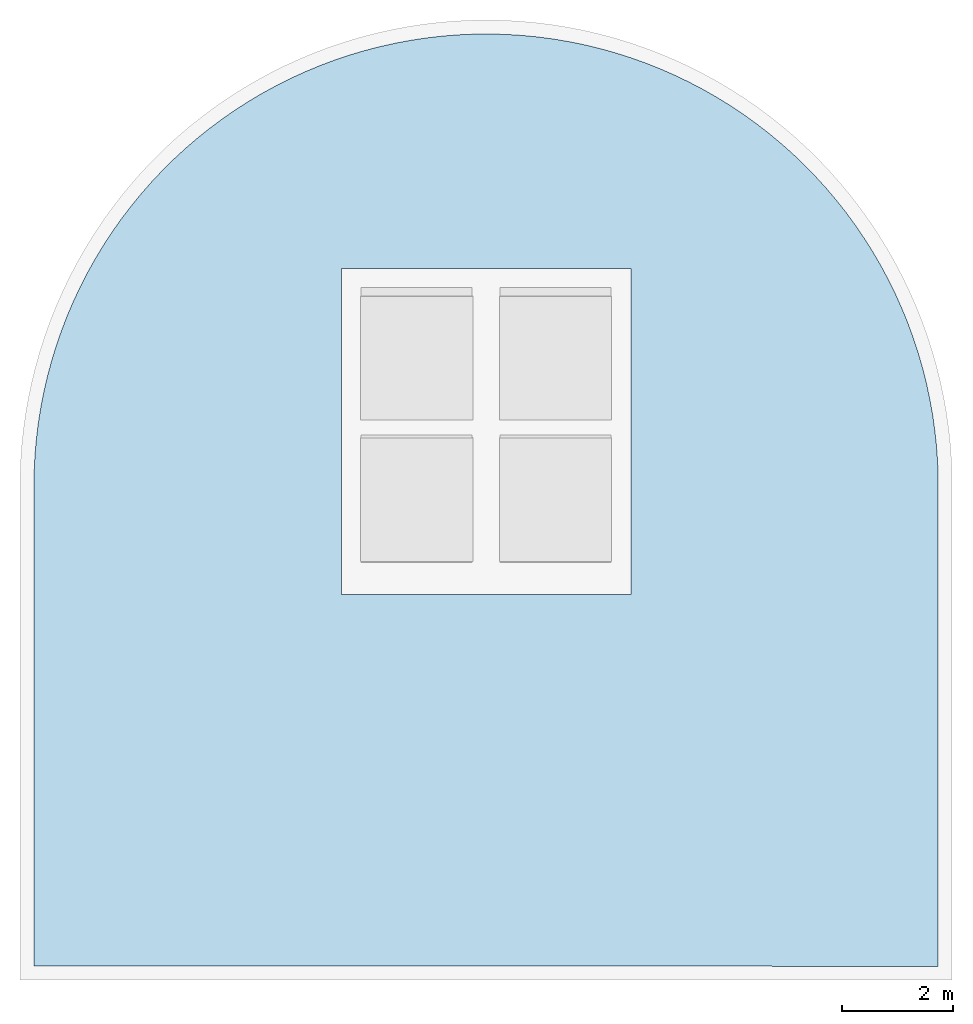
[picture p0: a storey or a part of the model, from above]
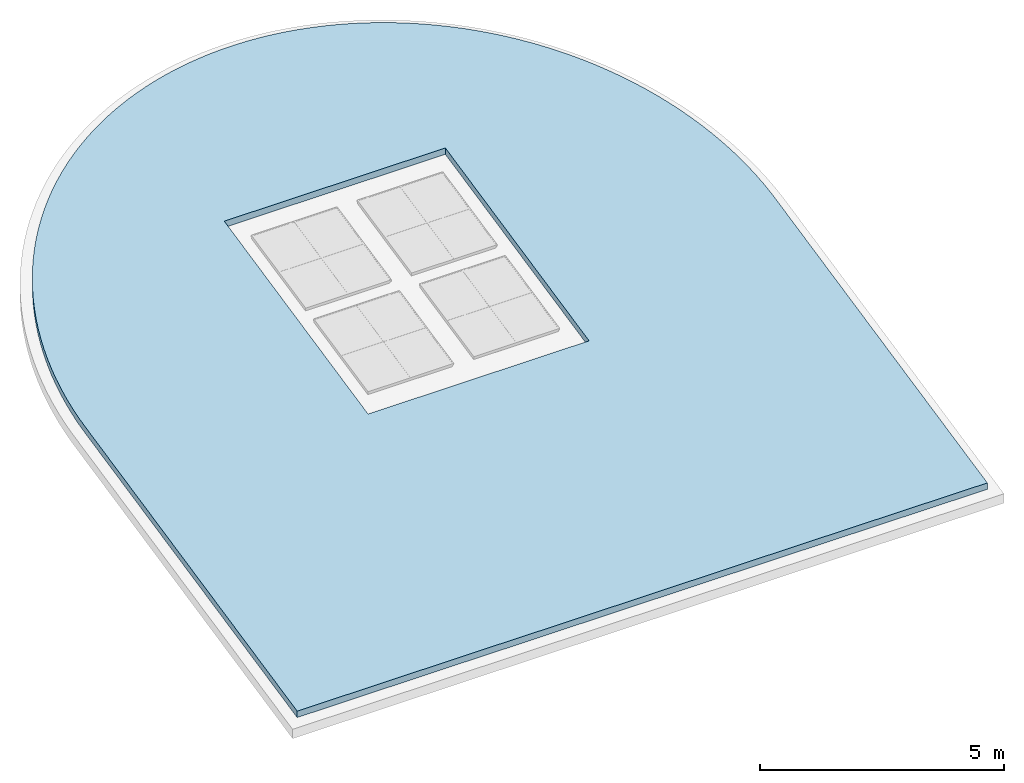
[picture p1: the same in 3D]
Properties of the parts of a building model (IFC4)

# File
Description: ViewDefinition [ReferenceView_V1.2], ExchangeRequirement [Architecture], Option [Elements to export: Visible elements (on all stories)], Option [Partial Structure Display: Entire Model], Option [IFC Domain: All], Option [Structural Function: All Elements], Option [Convert Grid elements: On], Option [Convert IFC Annotations and Archicad 2D elements: Off], Option [Convert 2D symbols of Doors and Windows: Off], Option [Export geometries that Participates in Collision Detection only: On], Option [Split complex elements: Off], Option [Material Preservation: Explode where necessary], Option [IFC Model position: Survey Point and Project Origin], Option [Curtain Wall export mode: Single Element], Option [Railing export mode: Single Element], Option [Stair export mode: Single Element], Option [Properties To Export: All properties], Option [Space containment: On], Option [IFC Domain For Space Containment: All], Option [Geometry to type objects: Off], Option [Element Properties: Off], Option [Building Material Properties: Off], Option [Element Parameters: Off], Option [Component Parameters: Off], Option [IFC Base Quantities: On], Option [Door Window Parameters: On], Option [IFC Space boundaries: On], Option [Archicad Zone Categories as IFC Space classification data: Off], Option [Element Classifications: Off]
File name: C:\Users\micel\OneDrive\Dokumenty\ŠKOLA\!!4.LS!!\BAKALÁŘKA\Publikace\Nová složka\LES24-PST-ZZ-M3-Obalka_budovy.ifc
Time: 2024-05-24T10:02:17
Author: Architect
Organization: Building Designer Office
Written by: DDS_IFC v3.0
Made in: IFC file generated by Graphisoft Archicad 27.0.0 CZE FULL Windows version (IFC add-on version: 3001 CZE FULL).
Authorization: The authorising person

# IfcProject, Univerzitní lezecké centrum
Description: BIM projekt - bakalářská práce

# IfcSite, Exteriér
RefLatitude: 50, 1, 18, 339575; RefLongitude: 15, 46, 11, 568244; RefElevation: 221783 mm
Qto_SiteBaseQuantities - GrossPerimeter: 0 mm; GrossArea: 3562 m2

# IfcBuilding, Univerzitní lezecké centrum
Qto_BuildingBaseQuantities - GrossFloorArea: 0 m2

# IfcBuildingStorey: Podlaží:0,000 (6)
In: Univerzitní lezecké centrum
Qto_BuildingStoreyBaseQuantities - GrossFloorArea: 0 m2
Name | LongName | Elevation (mm) | NetHeight (mm) = GrossHeight (mm)
1.PP | 1.PP | -3350 | 3350
2.NP | 2.NP | 3200 | 3200
3.NP | 3.NP | 6400 | 3200
1.NP | 1.NP | 0 | 3200
4.NP | 4.NP | 9600 | 3200
Střecha | Střecha | 12800 | 8000

# IfcCurtainWall: Typ lehkého obvodového pláště (8)
Pset_CurtainWallCommon - Status: EXISTING
Parametry - Druh zasklení: Izolační trojsklo, Ug=0,6 W/m2K; Bezpečnostní; Materiál okna: Hliníkové LOP; Barva rámu: Celadonově zelená RAL 6019
Pset_ManufacturerOccurrence - AcquisitionDate: DD.MM.RRRR
Qto_CurtainWallQuantities - Height: 2500 mm
Name | In | Material | Způsob otevírání | Width (mm) | Length (mm) | GrossSideArea (m2) = NetSideArea (m2)
4 x LOP01 | 1.NP | Sklo (4), Hliník (12) | Pevné | 50 | 2507.41 | 6.26851
2 x LOP01 | 1.NP | Sklo (4), Hliník (13) | Sklápěcí | 50 | 2507.41 | 6.26851
LOP01 | 1.NP | Hliník (22), Sklo (8), Ocel - nerez | Otočné | 50 | 2530.4 | 6.32599
LOP01 | 3.NP | Sklo (6), Hliník (17), Ocel - nerez | Otočné | 300 | 4500.17 | 11.2504

# IfcOpeningElement (33)
Name | In | Depth (mm) | Height (mm) | Width (mm) | Area (m2) | Volume (m3)
 | 1.PP | 160 | 0 | 0 | 0 | 0
 | 1.NP | 200 | 2200 | 1500 | 3.3 | 0
7 x  | 1.NP | 200 | 0 | 0 | 0 | 0
2 x Pr01 | 2.NP | 200 | 740 | 940 | 0.6956 | 0.13912 | Pset_OpeningElementCommon - Status: EXISTING
13 x  | 3.NP | 200 | 0 | 0 | 0 | 0
Pr02 | 3.NP | 200 | 830 | 930 | 0.7719 | 0.15438 | Pset_OpeningElementCommon - Status: EXISTING
Pr03 | 3.NP | 200 | 575 | 810.473 | 0.466022 | 0.0930961 | Pset_OpeningElementCommon - Status: EXISTING
2 x  | 4.NP | 200 | 0 | 0 | 0 | 0
Pr04 | 4.NP | 200 | 245.826 | 810.473 | 0.199235 | 0.039847 | Pset_OpeningElementCommon - Status: EXISTING
4 x O05 | Střecha |  | 2250 | 2000 | 4.5 | 1.0215

# IfcSlab: !Podlaha spádovaná - terasy - TI + HI vrstva 166 (8)
In: 4.NP
Type - PredefinedType: ROOF
Description: Desky z expandovaného pěnového polystyrenu, napětí v tlaku při 10% deformaci 150 kPa, součinitel tepelné vodivosti 0,035 W/mK; Material: TPO fólie ochranná, Geotextilie 200 g/m2, Hydroizolace - TPO fólie, Tepelná izolace - polystyren EPS podlahy
Parametry - Součinitel tepelné vodivosti: 0,035 W/mK; Objemová hmotnost: 25 kg/m3
Pset_SlabCommon - Status: EXISTING; LoadBearing: yes
Qto_SlabBaseQuantities - Width: 166 mm; TPO fólie ochranná, Width: 2 mm; Geotextilie 200 g/m2, Width: 2 mm; Hydroizolace - TPO fólie, Width: 2 mm; Tepelná izolace - polystyren EPS podlahy, Width: 160 mm
Pset_ManufacturerOccurrence - AcquisitionDate: DD.MM.RRRR
Name | Perimeter (mm) | GrossArea (m2) = NetArea (m2) | GrossVolume (m3) = NetVolume (m3)
 | 21271.8 | 19.4968 | 3.23647
 | 10319.8 | 2.0388 | 0.338443
 | 10319.2 | 2.03883 | 0.338447
 | 16973.6 | 14.4215 | 2.39397
 | 12627.2 | 9.72822 | 1.61489
 | 21273.1 | 19.4974 | 3.23657
S02 | 16978.1 | 14.427 | 2.39489
 | 12627.4 | 9.72817 | 1.61488

# IfcSlab: !Podlaha spádovaná - terasy - podložky + dlažba 135, S02
In: 4.NP
Type - PredefinedType: FLOOR
Description: Mrazuvzdorná betonová dlažba z vybrolisovaného betonu, hmotnost 111 kg/m2, rozměr 400x400 mm na podložkách: nastavitelné terčové podložky, kladeny na přířez HI; Material: Betonová dlažba, Rektifikální podložky
Pset_ManufacturerOccurrence - AcquisitionDate: DD.MM.RRRR
Qto_SlabBaseQuantities - Width: 135 mm; Perimeter: 40727.7 mm; GrossArea: 97.0699 m2; NetArea: 88.2021 m2; GrossVolume: 9.45602 m3; NetVolume: 8.25886 m3; Betonová dlažba, Width: 50 mm; Rektifikální podložky, Width: 85 mm
Pset_SlabCommon - Status: EXISTING; LoadBearing: yes

# IfcSlab: !Podlaha spádovaná - terasy - spádová vrstva EPS 205, S02
In: 4.NP
Type - PredefinedType: FLOOR
Description: Spádové klíny z expandovaného pěnového polystyrenu ve spádu 2%, základní rozměr desky 1x1 m, součinitel tepelné vodivosti 0,035 W/ mK, napětí v tlaku při 10% deformaci 150 kPa; Material: Tepelná izolace - polystyren EPS spádová vrstva, Parozábrana - modifikovaný asfaltový pás samolepící, Penetrační nátěr asfaltový
Parametry - Součinitel tepelné vodivosti: 0,035 W/ mK; Tloušťka: 25 kg/m3
Pset_SlabCommon - Status: EXISTING; LoadBearing: yes
Qto_SlabBaseQuantities - Width: 205 mm; Perimeter: 41132.7 mm; GrossArea: 9.06309 m2; NetArea: 0.0147011 m2; GrossVolume: 8.83294 m3; NetVolume: 6.97802 m3; Tepelná izolace - polystyren EPS spádová vrstva, Width: 200 mm; Parozábrana - modifikovaný asfaltový pás samolepící, Width: 4 mm; Penetrační nátěr asfaltový, Width: 1 mm
Pset_ManufacturerOccurrence - AcquisitionDate: DD.MM.RRRR

# IfcSlab: !S01 - střešní souvrství na trapézovém plechu 227, S01
In: Střecha
Type - PredefinedType: ROOF
Description: Tuhé těžké desky z nehořlavé kamenné vlny, horní tuhá vrstva zabezpečuje mechanickou odolnost, desky jsou v celém objemu hydrofobizované, součinitel tepelné vodivosti 0,040 W/mK, loženy ve dvou vrstvách; Material: Geotextilie 300 g/m2, Hydroizolace - TPO fólie, Tepelná izolace - minerální vata, Tepelná izolace - minerální vata., Parozábrana - modifikovaný asfaltový pás samolepící
Parametry - Součinitel tepelné vodivosti: 0,040 W/mK; Objemová hmotnost: 80 kg/m3
Pset_SlabCommon - Status: EXISTING; LoadBearing: yes
Pset_ManufacturerOccurrence - AcquisitionDate: DD.MM.RRRR
Qto_SlabBaseQuantities - Width: 227 mm; Perimeter: 61684.8 mm; GrossArea: 266.179 m2; NetArea: 248.179 m2; GrossVolume: 60.3265 m3; NetVolume: 56.2405 m3; Geotextilie 300 g/m2, Width: 1.5 mm; Hydroizolace - TPO fólie, Width: 1.5 mm; Tepelná izolace - minerální vata, Width: 110 mm; Tepelná izolace - minerální vata., Width: 110 mm; Parozábrana - modifikovaný asfaltový pás samolepící, Width: 4 mm

# IfcSlab: Kačírek - frakce 16/32 157, S01
In: Střecha
Type - PredefinedType: ROOF
Description: Prané říční kamenivo 16/32, objemová hmotnost 1500 kg/m3; Material: Kačírek - frakce 16/32
Qto_SlabBaseQuantities - Width: 156.504 mm; Perimeter: 59874.6 mm; GrossArea: 250.739 m2; NetArea: 219.36 m2; GrossVolume: 39.2415 m3; NetVolume: 34.3307 m3; Kačírek - frakce 16/32, Width: 156.504 mm
Pset_ManufacturerOccurrence - AcquisitionDate: DD.MM.RRRR
Pset_SlabCommon - IsExternal: yes; Status: EXISTING

# IfcWall: Obvodová tepelná izolace - atika 100, St01*
In: 4.NP
Description: PIR desky, lepeno stvabení lepidlem, pevnost v tlaku při 10% deformaci 120 kPa, součinitel tepelné vodivosti 0,022 W/mK; Material: Tepelná izolace - PIR
Pset_WallCommon - Status: EXISTING; LoadBearing: yes
Parametry - Součinitel tepelné vodivosti: 0,022 W/m2K; Tloušťka izolace: 100; Objemová hmotnost: 60 kg/m3
Pset_ManufacturerOccurrence - AcquisitionDate: DD.MM.RRRR
Qto_WallBaseQuantities - Length: 24575.6 mm; Height: 1520 mm; Width: 100 mm; GrossFootprintArea: 2.49783 m2; NetFootprintArea: 2.49783 m2; GrossSideArea: 0 m2; NetSideArea: 0 m2; GrossVolume: 3.74665 m3; NetVolume: 3.74665 m3; Tepelná izolace - PIR, Width: 100 mm

# IfcWall: Obvodová tepelná izolace 200 (25)
Description: fasádní desky z čedičové minerální vlny, vhodná pro lepení stavebním lepidlem, lepené po obvodu a kotvené uprosřed desky, součinitel tepelné vodivosti 0,035 W/mK, vlákna orientovaná kolmo; Material: Tepelná izolace - minerální vata - obvodová izolace
Parametry - Tloušťka izolace: 200; Součinitel tepelné vodivosti: 0,035 W/mK; Objemová hmotnost: 100 kg/m3
Pset_ManufacturerOccurrence - AcquisitionDate: DD.MM.RRRR
Pset_WallCommon - Status: EXISTING
Qto_WallBaseQuantities - Width: 200 mm; GrossSideArea: 0 m2; NetSideArea: 0 m2; Tepelná izolace - minerální vata - obvodová izolace, Width: 200 mm
Name | In | LoadBearing | Length (mm) | Height (mm) | GrossFootprintArea (m2) = NetFootprintArea (m2) | GrossVolume (m3) | NetVolume (m3)
St01 | 1.NP | yes | 26075.2 | 2780 | 5.21557 | 14.4993 | 14.4993
2 x St01 | 1.NP | yes | 3700 | 2780 | 0.74 | 2.0572 | 2.0572
St01 | 1.NP | yes | 4999.99 | 2900 | 0.7 | 2.9 | 2.24
St01 | 1.NP | yes | 26075.2 | 2780 | 4.74499 | 6.78422 | 5.74894
St01 | 1.NP | yes | 4999.99 | 2900 | 1 | 2.9 | 2.9
St01 | 2.NP | yes | 3700 | 3200 | 0.74 | 2.368 | 2.08976
2 x St01 | 2.NP | yes | 5000.16 | 3200 | 1.00003 | 3.2001 | 3.2001
St01 | 2.NP | yes | 26074.9 | 3200 | 5.2155 | 16.6893 | 16.6893
St01 | 2.NP | yes | 3700 | 3200 | 0.74 | 2.368 | 2.368
St01 | 2.NP | yes | 26075.2 | 3200 | 5.21557 | 16.6898 | 16.6898
St01 | 3.NP | yes | 5000 | 3200 | 1.00026 | 3.20001 | 3.20001
St01 | 3.NP | yes | 26075.2 | 3320 | 5.21557 | 17.2981 | 15.7175
St01 | 3.NP | yes | 3700 | 3200 | 0.74 | 2.368 | 2.368
St01 | 3.NP | yes | 5000 | 3200 | 1.04 | 3.20204 | 3.20204
St01 | 3.NP | yes | 26075.2 | 3200 | 5.21557 | 16.6898 | 16.6898
St01 | 3.NP | yes | 3700 | 3200 | 0.74 | 2.368 | 2.12052
St03 | 4.NP | no | 16600 | 3059.89 | 3.2 | 9.72322 | 7.49822
St01 | 4.NP | yes | 5100 | 4071.67 | 0.74 | 3.6121 | 3.0121
St01* | 4.NP | yes | 25675.2 | 1200 | 5.13556 | 6.16268 | 6.16268
St01 | 4.NP | yes | 5100 | 4071.67 | 1.04 | 3.65978 | 3.65978
St01 | 4.NP | yes | 3700 | 4978.13 | 0.74 | 3.39283 | 3.39283
St01 | 4.NP | yes | 26075.2 | 6763.81 | 5.21557 | 31.8222 | 31.8222
St01 | 4.NP | yes | 3700 | 4978.13 | 0.577905 | 3.39283 | 3.35298

# IfcWall: Obvodová tepelná izolace podzemní 160 (16)
In: 1.PP
Description: Desky z extrudovaného polystyrenu s uzavřenou povrchovou strukturou, lepeno PU pěnou, pevnost v tlaku při 10% deformaci 150 kPa, součinitel tepelné vodivosti 0,034 W/mK; Material: Tepelná izolace - XPS - obvodová izolace
Parametry - Součinitel tepelné vodivosti: 0,034 W/mK; Tloušťka izolace: 160; Objemová hmotnost: 30 kg/m3
Pset_WallCommon - Status: EXISTING
Pset_ManufacturerOccurrence - AcquisitionDate: DD.MM.RRRR
Qto_WallBaseQuantities - Width: 160 mm; GrossSideArea: 0 m2; NetSideArea: 0 m2; Tepelná izolace - XPS - obvodová izolace, Width: 160 mm
Name | Length (mm) | Height (mm) | GrossFootprintArea (m2) = NetFootprintArea (m2) | GrossVolume (m3) | NetVolume (m3)
St02 | 3075 | 4220 | 0.492 | 2.07624 | 2.07624
St02 | 3162.11 | 4220 | 0.505991 | 2.13528 | 2.13528
2 x St02 | 3700 | 4220 | 0.592 | 2.49824 | 2.49824
St02 | 5000 | 4220 | 0.8 | 3.376 | 3.376
St02 | 26012.4 | 4220 | 4.1624 | 17.0732 | 16.4421
St02 | 425 | 4220 | 0.068 | 0.28696 | 0.28696
6 x St02 | 324.755 | 300 | 0.0519653 | 0.0155896 | 0.0155896
St02 | 1500 | 3819.98 | 0.24 | 0.916795 | 0.916795
St02 | 3161.84 | 4220 | 0.505946 | 2.13509 | 2.13509
St02 | 19688.4 | 3920 | 3.15047 | 12.3493 | 12.3493

# IfcWindow: V P 27 (4)
In: Střecha
Type - Window Lining Properties - LiningDepth: 50 mm; LiningThickness: 100 mm
OverallHeight: 2250 mm; OverallWidth: 2000 mm
Qto_WindowBaseQuantities - Height: 2250 mm; Width: 2000 mm; Perimeter: 8500 mm; Area: 4.5 m2
Pset_ManufacturerOccurrence - AcquisitionDate: DD.MM.RRRR
Parametry - Zasklení: Pevné, izolační trojsklo Ug=0,6 W/m2K; Materiál rámu: Hliníkové okno, lakovaný RAL 9007
Pset_WindowCommon - ThermalTransmittance: 0; Status: EXISTING
